VERSION 5.4 ;
NAMESCASESENSITIVE ON ;
BUSBITCHARS "[]" ;
DIVIDERCHAR "/" ;
UNITS
  DATABASE MICRONS 2000 ;
END UNITS
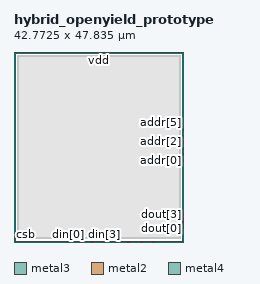
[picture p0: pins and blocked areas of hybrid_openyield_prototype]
MACRO hybrid_openyield_prototype
   CLASS BLOCK ;
   SIZE 42.7725 BY 47.8350 ;
   SYMMETRY X Y R90 ;
   PIN addr[0]
      DIRECTION INPUT ;
      PORT
         LAYER metal3 ;
         RECT 42.6125 20.1475 42.7725 20.6475 ;
      END
   END addr[0]
   PIN addr[1]
      DIRECTION INPUT ;
      PORT
         LAYER metal3 ;
         RECT 42.6125 21.7125 42.7725 22.2125 ;
      END
   END addr[1]
   PIN addr[2]
      DIRECTION INPUT ;
      PORT
         LAYER metal3 ;
         RECT 42.6125 23.2775 42.7725 23.7775 ;
      END
   END addr[2]
   PIN addr[3]
      DIRECTION INPUT ;
      PORT
         LAYER metal3 ;
         RECT 42.6125 24.8425 42.7725 25.3425 ;
      END
   END addr[3]
   PIN addr[4]
      DIRECTION INPUT ;
      PORT
         LAYER metal3 ;
         RECT 42.6125 26.4075 42.7725 26.9075 ;
      END
   END addr[4]
   PIN addr[5]
      DIRECTION INPUT ;
      PORT
         LAYER metal3 ;
         RECT 42.6125 27.9725 42.7725 28.4725 ;
      END
   END addr[5]
   PIN clk
      DIRECTION INPUT ;
      PORT
         LAYER metal2 ;
         RECT 0.0000 0.2425 0.1600 0.7425 ;
      END
   END clk
   PIN csb
      DIRECTION INPUT ;
      PORT
         LAYER metal2 ;
         RECT 0.0000 0.9925 0.1600 1.4925 ;
      END
   END csb
   PIN din[0]
      DIRECTION INPUT ;
      PORT
         LAYER metal2 ;
         RECT 13.3700 0.0000 13.8700 0.1600 ;
      END
   END din[0]
   PIN din[1]
      DIRECTION INPUT ;
      PORT
         LAYER metal2 ;
         RECT 16.4300 0.0000 16.9300 0.1600 ;
      END
   END din[1]
   PIN din[2]
      DIRECTION INPUT ;
      PORT
         LAYER metal2 ;
         RECT 19.4900 0.0000 19.9900 0.1600 ;
      END
   END din[2]
   PIN din[3]
      DIRECTION INPUT ;
      PORT
         LAYER metal2 ;
         RECT 22.5500 0.0000 23.0500 0.1600 ;
      END
   END din[3]
   PIN din[4]
      DIRECTION INPUT ;
      PORT
         LAYER metal2 ;
         RECT 25.6100 0.0000 26.1100 0.1600 ;
      END
   END din[4]
   PIN din[5]
      DIRECTION INPUT ;
      PORT
         LAYER metal2 ;
         RECT 28.6700 0.0000 29.1700 0.1600 ;
      END
   END din[5]
   PIN din[6]
      DIRECTION INPUT ;
      PORT
         LAYER metal2 ;
         RECT 31.7300 0.0000 32.2300 0.1600 ;
      END
   END din[6]
   PIN din[7]
      DIRECTION INPUT ;
      PORT
         LAYER metal2 ;
         RECT 34.7900 0.0000 35.2900 0.1600 ;
      END
   END din[7]
   PIN dout[0]
      DIRECTION OUTPUT ;
      PORT
         LAYER metal3 ;
         RECT 42.6125 3.2875 42.7725 3.5375 ;
      END
   END dout[0]
   PIN dout[1]
      DIRECTION OUTPUT ;
      PORT
         LAYER metal3 ;
         RECT 42.6125 3.8375 42.7725 4.0875 ;
      END
   END dout[1]
   PIN dout[2]
      DIRECTION OUTPUT ;
      PORT
         LAYER metal3 ;
         RECT 42.6125 4.3875 42.7725 4.6375 ;
      END
   END dout[2]
   PIN dout[3]
      DIRECTION OUTPUT ;
      PORT
         LAYER metal3 ;
         RECT 42.6125 4.9375 42.7725 5.1875 ;
      END
   END dout[3]
   PIN dout[4]
      DIRECTION OUTPUT ;
      PORT
         LAYER metal3 ;
         RECT 42.6125 5.4875 42.7725 5.7375 ;
      END
   END dout[4]
   PIN dout[5]
      DIRECTION OUTPUT ;
      PORT
         LAYER metal3 ;
         RECT 42.6125 6.0375 42.7725 6.2875 ;
      END
   END dout[5]
   PIN dout[6]
      DIRECTION OUTPUT ;
      PORT
         LAYER metal3 ;
         RECT 42.6125 6.5875 42.7725 6.8375 ;
      END
   END dout[6]
   PIN dout[7]
      DIRECTION OUTPUT ;
      PORT
         LAYER metal3 ;
         RECT 42.6125 7.1375 42.7725 7.3875 ;
      END
   END dout[7]
   PIN gnd
      DIRECTION INOUT ;
      USE GROUND ;
      SHAPE ABUTMENT ;
      PORT
         LAYER metal4 ;
         RECT 0.0000 0.0500 42.7725 0.2000 ;
      END
   END gnd
   PIN vdd
      DIRECTION INOUT ;
      USE POWER ;
      SHAPE ABUTMENT ;
      PORT
         LAYER metal4 ;
         RECT 0.0000 47.6350 42.7725 47.7850 ;
      END
   END vdd
   PIN web
      DIRECTION INPUT ;
      PORT
         LAYER metal2 ;
         RECT 0.0000 1.7425 0.1600 2.2425 ;
      END
   END web
   OBS
      LAYER metal1 ;
         RECT 0.8000 0.8000 41.9725 47.0350 ;
      LAYER metal2 ;
         RECT 0.8000 0.8000 41.9725 47.0350 ;
      LAYER metal3 ;
         RECT 0.8000 0.8000 41.9725 47.0350 ;
      LAYER metal4 ;
         RECT 1.1200 1.1200 41.6525 46.7150 ;
   END
END hybrid_openyield_prototype
END LIBRARY
